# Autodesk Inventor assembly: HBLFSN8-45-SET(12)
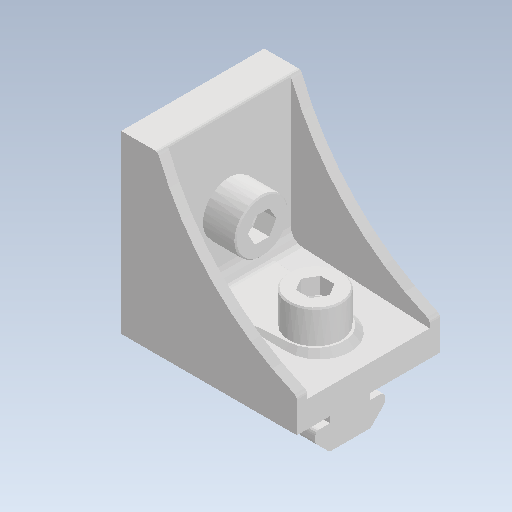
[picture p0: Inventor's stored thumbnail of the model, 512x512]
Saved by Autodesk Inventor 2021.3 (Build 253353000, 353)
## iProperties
Created: 2022-02
Part Number: HBLFSN8-45-SET(12)
Document SubType Name: Assembly
Designer: kengo
Author: kengo
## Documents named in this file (4)
- C:\Users\kengo\Documents\S2S_frame\SDC345\frame_misumi_ver12\HBLFSN8-45-SET(12).iam
- C:\Users\kengo\Documents\S2S_frame\SDC345\frame_misumi_ver12\HBLFSN8-45.ipt
- C:\Users\kengo\Documents\S2S_frame\SDC345\frame_misumi_ver12\HNTT8-8.ipt
- C:\Users\kengo\Documents\S2S_frame\SDC345\frame_misumi_ver12\CBM8-20.ipt
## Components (5 placed, 3 different names)
1. HBLFSN8-45
2. HNTT8-8
3. CBM8-20
4. HNTT8-8:1
5. CBM8-20:1
